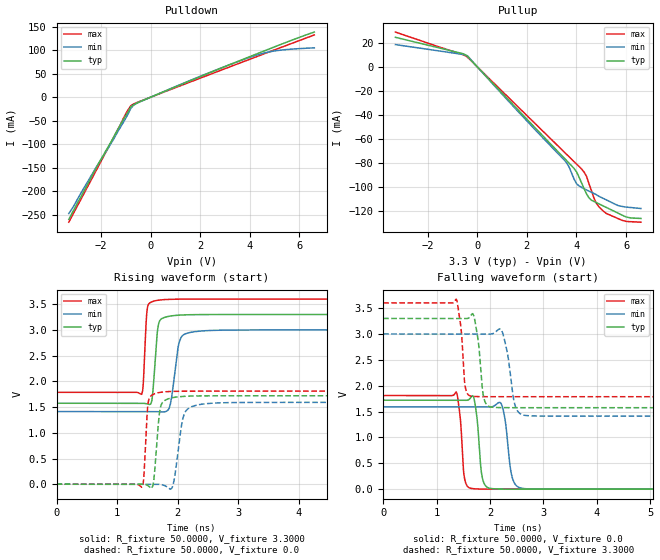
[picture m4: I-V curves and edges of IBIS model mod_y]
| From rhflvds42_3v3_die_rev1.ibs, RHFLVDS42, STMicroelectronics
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|   Model mod_y
[Model]   mod_y
Model_type  3-state
Polarity   Non-Inverting
Enable   Active-High
Vmeas  =   1.650V
Cref   =   10pF
C_comp   0.486pF   0.402pF   0.584pF
[Temperature Range]  25.0000   0.1250k   -55.0000
[Voltage Range]   3.3000V   3.0000V   3.6000V
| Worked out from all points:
|   slope of the pulldown table from 0 to 0.495 V, typ, clamps not added: 45.4 ohm
|   slope of the pullup table from 0 to 0.495 V, typ, clamps not added: 45.8 ohm
|   rising waveform, R_fixture 50.0000, V_fixture 3.3000: 20-80 % time 64.8ps typ, 105ps min, 43.5ps max; typ from 1.57 V to 3.3 V
|   rising waveform, R_fixture 50.0000, V_fixture 0.0: 20-80 % time 71.8ps typ, 113ps min, 48.4ps max; typ from 0 V to 1.72 V
|   falling waveform, R_fixture 50.0000, V_fixture 0.0: 20-80 % time 80.1ps typ, 104ps min, 68.6ps max; typ from 1.72 V to 0 V
|   falling waveform, R_fixture 50.0000, V_fixture 3.3000: 20-80 % time 93ps typ, 128ps min, 75.7ps max; typ from 3.3 V to 1.57 V
[Pulldown]
|Voltage   I(typ)   I(min)   I(max)
-3.3V     -260.2mA   -247.8mA   -266.2mA
-3.1V     -240.2mA   -231.6mA   -246.2mA
-2.1V     -141.2mA   -141.2mA   -146.4mA
-1.5V     -85.78mA   -90.01mA   -86.44mA
-1V       -38.88mA   -44.46mA   -34.93mA
-800mV    -20.64mA   -23.88mA   -18.26mA
-600mV    -13.39mA   -14.2mA    -12.27mA
600mV     13.21mA    13.64mA    12.2mA
2.6V      56.67mA    57.22mA    52.69mA
4.1V      88.56mA    86.74mA    82.85mA
5.1V      109.3mA    99.26mA    102.8mA
6.6V      138.7mA    105.1mA    132.6mA
[Pullup]
|Voltage   I(typ)   I(min)   I(max)
-3.3V     24.51mA    18.46mA    28.84mA
-400mV    8.749mA    9.224mA    8.101mA
3.5V      -75.7mA    -77.24mA   -70.66mA
3.7V      -79.97mA   -83.07mA   -74.68mA
3.9V      -84.38mA   -93.09mA   -78.7mA
4.1V      -91.46mA   -98.85mA   -82.72mA
4.4V      -105.3mA   -102.2mA   -90.73mA
4.5V      -108.7mA   -103.2mA   -96.78mA
4.8V      -112.8mA   -106.2mA   -113.3mA
5.1V      -115.8mA   -109.5mA   -120.2mA
5.9V      -123.8mA   -116.2mA   -127.9mA
6.6V      -126mA     -117.7mA   -129.1mA
|[GND_clamp]
|Voltage   I(typ)   I(min)   I(max)
|  -3.30   -78.2120MA   -55.2710MA   -0.1112GA
|  -3.23   -75.4270MA   -53.1860MA   -0.1074GA
|  -3.16   -72.6430MA   -51.1010MA   -0.1036GA
|  -3.09   -69.8590MA   -49.0160MA   -99.8120MA
|  -3.02   -67.0750MA   -46.9310MA   -96.0070MA
|  -2.95   -64.2910MA   -44.8470MA   -92.2020MA
|  -2.88   -61.5070MA   -42.7620MA   -88.3960MA
|  -2.81   -58.7230MA   -40.6770MA   -84.5910MA
|  -2.74   -55.9380MA   -38.5920MA   -80.7860MA
|  -2.67   -53.1540MA   -36.5070MA   -76.9810MA
|  -2.60   -50.3700MA   -34.4220MA   -73.1760MA
|  -2.53   -47.5860MA   -32.3370MA   -69.3710MA
|  -2.46   -44.8020MA   -30.2520MA   -65.5660MA
|  -2.39   -42.0180MA   -28.1680MA   -61.7600MA
|  -2.32   -39.2340MA   -26.0830MA   -57.9550MA
|  -2.25   -36.4490MA   -23.9980MA   -54.1500MA
|  -2.18   -33.6650MA   -21.9130MA   -50.3450MA
|  -2.11   -30.8810MA   -19.8280MA   -46.5400MA
|  -2.04   -28.0970MA   -17.7430MA   -42.7350MA
|  -1.97   -25.3130MA   -15.6580MA   -38.9300MA
|  -1.90   -22.5290MA   -13.5730MA   -35.1240MA
|  -1.83   -19.7450MA   -11.4890MA   -31.3190MA
|  -1.76   -16.9610MA   -9.4037MA   -27.5140MA
|  -1.69   -14.1760MA   -7.3189MA   -23.7090MA
|  -1.62   -11.3920MA   -5.2340MA   -19.9040MA
|  -1.55   -8.6081MA   -3.1491MA   -16.0990MA
|  -1.48   -5.8239MA   -1.6562MA   -12.2940MA
|  -1.41   -3.0398MA   -0.5828MA   -8.4884MA
|  -1.34   -1.1270MA   -72.1680kA   -4.6833MA
|  -1.27   -0.1045MA   -8.7998kA   -1.3254MA
|  -1.20   -6.2897kA   -1.0731kA   -51.1050kA
|  -1.13   -0.3785kA   -0.1309kA   -1.0946kA
|  -1.06   -22.8120A   -15.9930A   -23.4910A
|  -0.99   -1.4001A   -1.9765A   -0.5309A
|  -0.92   -0.1080A   -0.2641A   -34.7740mA
|  -0.85   -27.1120mA   -52.5120mA   -20.7010mA
|  -0.78   -19.4430mA   -24.1420mA   -17.4570mA
|  -0.71   -16.5560mA   -18.3010mA   -15.0570mA
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[Ramp]
| variable   typ   min   max
dV/dt_r   1.0319/98.6093p   0.9548/0.1324n   1.0861/71.5827p
dV/dt_f   1.0352/0.1159n   0.9524/0.1536n   1.0880/0.1167n
R_load = 50.0000
[Rising Waveform]
R_fixture= 50.0000
V_fixture= 3.3000
V_fixture_min= 3.0000
V_fixture_max= 3.6000
|time   V(typ)   V(min)   V(max)
0s        1.575V     1.413V     1.787V
1.408ns   1.576V     1.413V     1.749V
1.504ns   1.558V     1.413V     3.44V
1.576ns   1.629V     1.413V     3.547V
1.648ns   2.708V     1.412V     3.571V
1.704ns   3.173V     1.408V     3.581V
1.864ns   3.266V     1.485V     3.594V
2.024ns   3.287V     2.746V     3.598V
2.2ns     3.295V     2.949V     3.599V
8ns       3.3V       3V         3.6V
[Rising Waveform]
R_fixture= 50.0000
V_fixture= 0.0
V_fixture_min= 0.0
V_fixture_max= 0.0
|time   V(typ)   V(min)   V(max)
0s        8.562nV    2.807uV    749.2pV
1.416ns   2.048mV    -34.58uV   -56.99mV
1.44ns    525uV      -41.48uV   100.4mV
1.52ns    -34.88mV   76.5uV     1.619V
1.608ns   84.24mV    1.639mV    1.753V
1.688ns   1.244V     88.43uV    1.781V
1.912ns   1.682V     -60.96mV   1.805V
2.104ns   1.708V     1.343V     1.809V
2.328ns   1.717V     1.541V     1.81V
8ns       1.72V      1.591V     1.81V
[Falling Waveform]
R_fixture= 50.0000
V_fixture= 0.0
V_fixture_min= 0.0
V_fixture_max= 0.0
|time   V(typ)   V(min)   V(max)
0s        1.72V      1.591V     1.81V
1.368ns   1.72V      1.591V     1.882V
1.52ns    1.719V     1.591V     229.4mV
1.648ns   1.781V     1.591V     14.34mV
1.856ns   224.9mV    1.591V     1.597mV
1.984ns   19.73mV    1.588V     481.3uV
2.232ns   1.648mV    1.598V     55.72uV
2.408ns   339.1uV    262.3mV    12.36uV
2.592ns   68.26uV    17.68mV    2.019uV
8ns       -161.2nV   2.745uV    -1.079uV
[Falling Waveform]
R_fixture= 50.0000
V_fixture= 3.3000
V_fixture_min= 3.0000
V_fixture_max= 3.6000
|time   V(typ)   V(min)   V(max)
0s        3.3V       3V         3.6V
1.368ns   3.3V       3V         3.675V
1.536ns   3.298V     3V         1.984V
1.64ns    3.352V     3V         1.8V
1.88ns    1.788V     3V         1.787V
1.992ns   1.594V     2.997V     1.787V
2.224ns   1.576V     3.056V     1.787V
2.464ns   1.575V     1.642V     1.787V
2.624ns   1.575V     1.433V     1.787V
8ns       1.575V     1.413V     1.787V
